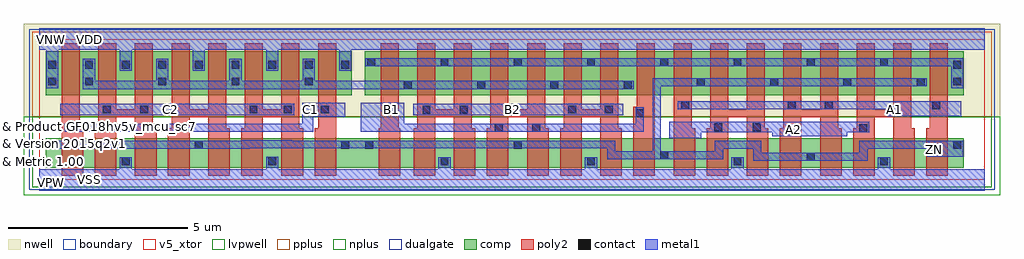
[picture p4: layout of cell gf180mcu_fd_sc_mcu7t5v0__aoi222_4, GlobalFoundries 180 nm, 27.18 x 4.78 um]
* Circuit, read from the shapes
.subckt gf180mcu_fd_sc_mcu7t5v0__aoi222_4 A1 A2 B1 B2 C1 C2 VDD VNW VSS ZN
XM1 n1 C1 ZN VSUBS nfet_05v0 w=0.82u l=0.6u
XM2 VSS C2 n1 VSUBS nfet_05v0 w=0.82u l=0.6u
XM3 n2 C2 VSS VSUBS nfet_05v0 w=0.82u l=0.6u
XM4 ZN C1 n2 VSUBS nfet_05v0 w=0.82u l=0.6u
XM5 n3 C1 ZN VSUBS nfet_05v0 w=0.82u l=0.6u
XM6 VSS C2 n3 VSUBS nfet_05v0 w=0.82u l=0.6u
XM7 n4 C2 VSS VSUBS nfet_05v0 w=0.82u l=0.6u
XM8 ZN C1 n4 VSUBS nfet_05v0 w=0.82u l=0.6u
XM9 n5 B1 ZN VSUBS nfet_05v0 w=0.82u l=0.6u
XM10 VSS B2 n5 VSUBS nfet_05v0 w=0.82u l=0.6u
XM11 n6 B2 VSS VSUBS nfet_05v0 w=0.82u l=0.6u
XM12 ZN B1 n6 VSUBS nfet_05v0 w=0.82u l=0.6u
XM13 n7 B1 ZN VSUBS nfet_05v0 w=0.82u l=0.6u
XM14 VSS B2 n7 VSUBS nfet_05v0 w=0.82u l=0.6u
XM15 n8 B2 VSS VSUBS nfet_05v0 w=0.82u l=0.6u
XM16 ZN B1 n8 VSUBS nfet_05v0 w=0.82u l=0.6u
XM17 n9 A1 ZN VSUBS nfet_05v0 w=0.82u l=0.6u
XM18 VSS A2 n9 VSUBS nfet_05v0 w=0.82u l=0.6u
XM19 n10 A2 VSS VSUBS nfet_05v0 w=0.82u l=0.6u
XM20 ZN A1 n10 VSUBS nfet_05v0 w=0.82u l=0.6u
XM21 n11 A1 ZN VSUBS nfet_05v0 w=0.82u l=0.6u
XM22 VSS A2 n11 VSUBS nfet_05v0 w=0.82u l=0.6u
XM23 n12 A2 VSS VSUBS nfet_05v0 w=0.82u l=0.6u
XM24 ZN A1 n12 VSUBS nfet_05v0 w=0.82u l=0.6u
XM25 n13 C1 VDD VNW pfet_05v0 w=1.22u l=0.5u m=4
XM26 VDD C2 n13 VNW pfet_05v0 w=1.22u l=0.5u m=4
XM27 n13 B1 n14 VNW pfet_05v0 w=1.22u l=0.5u m=4
XM28 n14 B2 n13 VNW pfet_05v0 w=1.22u l=0.5u m=4
XM29 ZN A1 n14 VNW pfet_05v0 w=1.22u l=0.5u m=4
XM30 n14 A2 ZN VNW pfet_05v0 w=1.22u l=0.5u m=4
.ends

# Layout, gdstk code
import gdstk
lib = gdstk.Library(unit=1e-6, precision=1e-09)
def R(c, l, rs):  # rectangles x0, y0, x1, y1
    for r in rs: c.add(gdstk.rectangle(r[:2], r[2:], *l))
def A(c, l, x, y, w, h, nx, ny, dx, dy):  # array of equal rectangles
    R(c, l, [(x+i*dx, y+j*dy, x+i*dx+w, y+j*dy+h) for i in range(nx) for j in range(ny)])
def P(c, l, *ps):  # polygons
    for p in ps: c.add(gdstk.Polygon(p, *l))
boundary = (0, 0)
nwell = (21, 0)
comp = (22, 0)
poly2 = (30, 0)
pplus = (31, 0)
nplus = (32, 0)
contact = (33, 0)
metal1 = (34, 0)
dualgate = (55, 0)
v5_xtor = (112, 1)
lvpwell = (204, 0)

gf180mcu_fd_sc_mcu7t5v0_ = lib.new_cell('gf180mcu_fd_sc_mcu7t5v0__aoi222_4')
R(gf180mcu_fd_sc_mcu7t5v0_, boundary, [(0,0,26.32,3.92)])
R(gf180mcu_fd_sc_mcu7t5v0_, nwell, [(-0.43,1.76,26.75,4.35)])
R(gf180mcu_fd_sc_mcu7t5v0_, comp, [(0.18,0.34,25.74,1.16), (0.18,2.36,8.7,3.58), (9.06,2.36,25.74,3.58)])
P(gf180mcu_fd_sc_mcu7t5v0_, poly2, [(0.62,0.12),(0.62,3.8),(1.12,3.8),(1.12,1.44),(1.22,1.44),(1.22,0.12)],
  [(1.54,0.12),(1.54,1.44),(1.64,1.44),(1.64,3.8),(2.14,3.8),(2.14,1.97),(2.66,1.97),(2.66,3.8),(3.16,3.8),(3.16,1.44),(3.26,1.44),(3.26,0.12),(2.66,0.12),(2.66,1.74),(2.14,1.74),(2.14,0.12)],
  [(3.58,0.12),(3.58,1.44),(3.68,1.44),(3.68,3.8),(4.18,3.8),(4.18,1.97),(4.7,1.97),(4.7,3.8),(5.2,3.8),(5.2,1.44),(5.3,1.44),(5.3,0.12),(4.7,0.12),(4.7,1.74),(4.18,1.74),(4.18,0.12)],
  [(5.62,0.12),(5.62,1.44),(5.72,1.44),(5.72,3.8),(6.22,3.8),(6.22,1.97),(6.74,1.97),(6.74,3.8),(7.24,3.8),(7.24,1.44),(7.34,1.44),(7.34,0.12),(6.74,0.12),(6.74,1.74),(6.22,1.74),(6.22,0.12)],
  [(7.66,0.12),(7.66,1.44),(7.76,1.44),(7.76,3.8),(8.26,3.8),(8.26,0.12)],
  [(9.45,0.12),(9.45,1.44),(9.5,1.44),(9.5,3.8),(10,3.8),(10,1.44),(10.05,1.44),(10.05,0.12)],
  [(10.42,0.12),(10.42,1.44),(10.52,1.44),(10.52,3.8),(11.02,3.8),(11.02,1.97),(11.54,1.97),(11.54,3.8),(12.04,3.8),(12.04,1.44),(12.14,1.44),(12.14,0.12),(11.54,0.12),(11.54,1.74),(11.02,1.74),(11.02,0.12)],
  [(12.46,0.12),(12.46,1.44),(12.56,1.44),(12.56,3.8),(13.06,3.8),(13.06,1.97),(13.58,1.97),(13.58,3.8),(14.08,3.8),(14.08,1.44),(14.18,1.44),(14.18,0.12),(13.58,0.12),(13.58,1.74),(13.06,1.74),(13.06,0.12)],
  [(14.5,0.12),(14.5,1.44),(14.6,1.44),(14.6,3.8),(15.1,3.8),(15.1,1.97),(15.62,1.97),(15.62,3.8),(16.12,3.8),(16.12,1.44),(16.22,1.44),(16.22,0.12),(15.62,0.12),(15.62,1.74),(15.1,1.74),(15.1,0.12)],
  [(16.54,0.12),(16.54,2.035),(16.64,2.035),(16.64,3.8),(17.14,3.8),(17.14,0.12)],
  [(17.66,0.12),(17.66,3.8),(18.16,3.8),(18.16,1.44),(18.26,1.44),(18.26,0.12)],
  [(18.58,0.12),(18.58,1.44),(18.68,1.44),(18.68,3.8),(19.18,3.8),(19.18,1.97),(19.7,1.97),(19.7,3.8),(20.2,3.8),(20.2,1.44),(20.3,1.44),(20.3,0.12),(19.7,0.12),(19.7,1.74),(19.18,1.74),(19.18,0.12)],
  [(20.62,0.12),(20.62,1.44),(20.72,1.44),(20.72,3.8),(21.22,3.8),(21.22,1.97),(21.74,1.97),(21.74,3.8),(22.24,3.8),(22.24,1.44),(22.34,1.44),(22.34,0.12),(21.74,0.12),(21.74,1.74),(21.22,1.74),(21.22,0.12)],
  [(22.66,0.12),(22.66,1.44),(22.76,1.44),(22.76,3.8),(23.26,3.8),(23.26,1.97),(23.78,1.97),(23.78,3.8),(24.28,3.8),(24.28,1.44),(24.38,1.44),(24.38,0.12),(23.78,0.12),(23.78,1.74),(23.26,1.74),(23.26,0.12)],
  [(24.7,0.12),(24.7,1.44),(24.8,1.44),(24.8,3.8),(25.3,3.8),(25.3,0.12)])
R(gf180mcu_fd_sc_mcu7t5v0_, pplus, [(-0.2,1.76,26.52,4.12)])
R(gf180mcu_fd_sc_mcu7t5v0_, nplus, [(-0.2,-0.2,26.52,1.76)])
A(gf180mcu_fd_sc_mcu7t5v0_, contact, 11.17, 0.41, 0.22, 0.22, 4, 1, 4.08, 0)
A(gf180mcu_fd_sc_mcu7t5v0_, contact, 0.25, 0.87, 0.22, 0.22, 3, 1, 4.08, 0)
A(gf180mcu_fd_sc_mcu7t5v0_, contact, 10.15, 2.535, 0.22, 0.22, 4, 1, 2.04, 0)
A(gf180mcu_fd_sc_mcu7t5v0_, contact, 18.31, 2.61, 0.22, 0.22, 4, 1, 2.04, 0)
A(gf180mcu_fd_sc_mcu7t5v0_, contact, 1.27, 2.63, 0.22, 0.22, 4, 1, 2.04, 0)
A(gf180mcu_fd_sc_mcu7t5v0_, contact, 0.25, 3.1, 0.22, 0.22, 9, 1, 1.02, 0)
A(gf180mcu_fd_sc_mcu7t5v0_, contact, 9.13, 3.165, 0.22, 0.22, 8, 1, 2.04, 0)
R(gf180mcu_fd_sc_mcu7t5v0_, contact, [(2.29,0.41,2.51,0.63), (6.37,0.41,6.59,0.63), (21.37,0.535,21.59,0.755), (17.29,0.575,17.51,0.795), (9.08,0.87,9.3,1.09), (13.21,0.87,13.43,1.09), (25.45,0.87,25.67,1.09), (22.83,1.33,23.05,1.55), (0.83,1.34,1.05,1.56), (3.81,1.34,4.03,1.56), (12.68,1.34,12.9,1.56), (13.73,1.34,13.95,1.56), (18.795,1.36,19.015,1.58), (19.87,1.36,20.09,1.58), (16.61,1.745,16.83,1.965), (10.67,1.845,10.89,2.065), (11.705,1.845,11.925,2.065), (1.77,1.85,1.99,2.07), (2.805,1.85,3.025,2.07), (5.85,1.85,6.07,2.07), (6.81,1.85,7.03,2.07), (7.83,1.85,8.05,2.07), (9.69,1.85,9.91,2.07), (14.73,1.85,14.95,2.07), (15.745,1.85,15.965,2.07), (17.87,1.97,18.09,2.19), (20.845,1.97,21.065,2.19), (21.87,1.97,22.09,2.19), (24.87,1.97,25.09,2.19), (0.25,2.63,0.47,2.85), (25.45,2.63,25.67,2.85), (25.45,3.1,25.67,3.32)])
R(gf180mcu_fd_sc_mcu7t5v0_, metal1, [(0.585,1.8,7.09,2.12), (10.415,1.8,16.255,2.12)])
P(gf180mcu_fd_sc_mcu7t5v0_, metal1, [(0.71,1.335),(0.71,1.565),(7.32,1.565),(7.32,2.15),(8.515,2.15),(8.515,1.76),(7.62,1.76),(7.62,1.335)],
  [(1.21,2.53),(1.21,3.38),(1.55,3.38),(1.55,2.76),(3.25,2.76),(3.25,3.38),(3.59,3.38),(3.59,2.76),(5.29,2.76),(5.29,3.38),(5.63,3.38),(5.63,2.76),(7.33,2.76),(7.33,3.38),(7.67,3.38),(7.67,2.76),(16.55,2.76),(16.55,2.53)],
  [(8.945,1.335),(8.945,2.15),(10.16,2.15),(10.16,1.565),(16.605,1.565),(16.605,2.025),(16.835,2.025),(16.835,1.335)],
  [(17.535,1.16),(17.535,1.615),(23.11,1.615),(23.11,1.325),(22.49,1.325),(22.49,1.22),(20.405,1.22),(20.405,1.325),(18.43,1.325),(18.43,1.16)],
  [(23.61,1.77),(23.61,1.965),(17.78,1.965),(17.78,2.195),(25.67,2.195),(25.67,1.77)],
  [(19.875,0.53),(19.875,0.865),(19.04,0.865),(19.04,0.57),(15.81,0.57),(15.81,0.865),(6.805,0.865),(6.805,0.87),(5.86,0.87),(5.86,0.865),(0.19,0.865),(0.19,1.095),(5.63,1.095),(5.63,1.1),(7.035,1.1),(7.035,1.095),(16.04,1.095),(16.04,0.8),(17.075,0.8),(17.075,2.835),(24.71,2.835),(24.71,2.605),(17.305,2.605),(17.305,0.8),(18.81,0.8),(18.81,1.095),(20.105,1.095),(20.105,0.76),(22.835,0.76),(22.835,1.095),(25.73,1.095),(25.73,0.65),(24.73,0.65),(24.73,0.865),(23.065,0.865),(23.065,0.53)],
  [(25.39,2.555),(25.39,3.16),(9.07,3.16),(9.07,3.39),(25.73,3.39),(25.73,2.555)],
  [(0,-0.3),(0,0.3),(2.23,0.3),(2.23,0.635),(2.57,0.635),(2.57,0.3),(6.31,0.3),(6.31,0.64),(6.65,0.64),(6.65,0.3),(11.11,0.3),(11.11,0.635),(11.45,0.635),(11.45,0.3),(15.19,0.3),(15.19,0.635),(15.53,0.635),(15.53,0.3),(19.27,0.3),(19.27,0.635),(19.61,0.635),(19.61,0.3),(23.35,0.3),(23.35,0.635),(23.69,0.635),(23.69,0.3),(26.32,0.3),(26.32,-0.3)],
  [(0.19,2.555),(0.19,3.62),(0,3.62),(0,4.22),(26.32,4.22),(26.32,3.62),(8.69,3.62),(8.69,3.04),(8.35,3.04),(8.35,3.62),(6.65,3.62),(6.65,3.04),(6.31,3.04),(6.31,3.62),(4.61,3.62),(4.61,3.04),(4.27,3.04),(4.27,3.62),(2.575,3.62),(2.575,3.04),(2.23,3.04),(2.23,3.62),(0.53,3.62),(0.53,2.555)])
R(gf180mcu_fd_sc_mcu7t5v0_, dualgate, [(-0.28,-0.28,26.6,4.2)])
R(gf180mcu_fd_sc_mcu7t5v0_, v5_xtor, [(0,0,26.32,3.92)])
R(gf180mcu_fd_sc_mcu7t5v0_, lvpwell, [(-0.43,-0.43,26.75,1.76)])
gf180mcu_fd_sc_mcu7t5v0_.add(gdstk.Label('A1', (23.8,1.96), layer=34, texttype=10))
gf180mcu_fd_sc_mcu7t5v0_.add(gdstk.Label('ZN', (24.92,0.84), layer=34, texttype=10))
gf180mcu_fd_sc_mcu7t5v0_.add(gdstk.Label('VSS', (1.4,0), layer=34, texttype=10))
gf180mcu_fd_sc_mcu7t5v0_.add(gdstk.Label('VDD', (1.4,3.92), layer=34, texttype=10))
gf180mcu_fd_sc_mcu7t5v0_.add(gdstk.Label('C2', (3.64,1.96), layer=34, texttype=10))
gf180mcu_fd_sc_mcu7t5v0_.add(gdstk.Label('C1', (7.56,1.96), layer=34, texttype=10))
gf180mcu_fd_sc_mcu7t5v0_.add(gdstk.Label('B2', (13.16,1.96), layer=34, texttype=10))
gf180mcu_fd_sc_mcu7t5v0_.add(gdstk.Label('B1', (9.8,1.96), layer=34, texttype=10))
gf180mcu_fd_sc_mcu7t5v0_.add(gdstk.Label('A2', (21,1.4), layer=34, texttype=10))
gf180mcu_fd_sc_mcu7t5v0_.add(gdstk.Label('& Vendor GLOBALFOUNDRIES', (0,2), layer=63, texttype=63))
gf180mcu_fd_sc_mcu7t5v0_.add(gdstk.Label('& Product GF018hv5v_mcu_sc7', (0,1.5), layer=63, texttype=63))
gf180mcu_fd_sc_mcu7t5v0_.add(gdstk.Label('& Version 2015q2v1', (0,1), layer=63, texttype=63))
gf180mcu_fd_sc_mcu7t5v0_.add(gdstk.Label('& Metric 1.00', (0,0.5), layer=63, texttype=63))
gf180mcu_fd_sc_mcu7t5v0_.add(gdstk.Label('VNW', (0.345,3.92), layer=21, texttype=10))
gf180mcu_fd_sc_mcu7t5v0_.add(gdstk.Label('VPW', (0.34,-0.085), layer=204, texttype=10))

lib.write_gds('gf180mcu_fd_sc_mcu7t5v0__aoi222_4.gds')
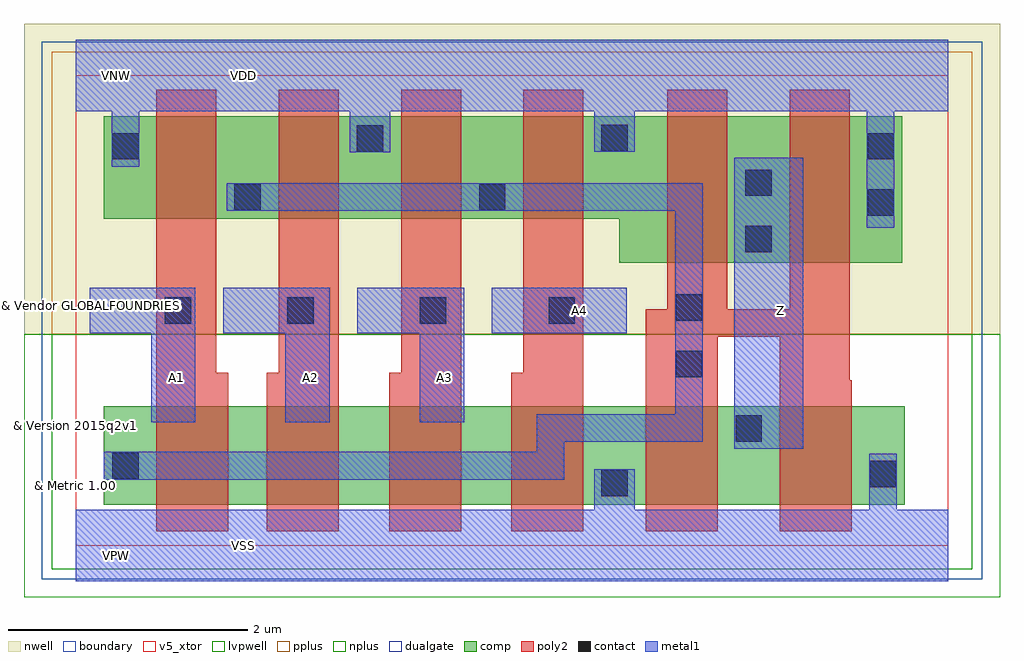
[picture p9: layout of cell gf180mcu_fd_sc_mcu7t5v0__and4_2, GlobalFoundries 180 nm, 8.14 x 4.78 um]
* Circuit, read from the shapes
.subckt gf180mcu_fd_sc_mcu7t5v0__and4_2 A1 A2 A3 A4 VDD VNW VSS Z
XM1 n1 A1 n2 VSUBS nfet_05v0 w=0.82u l=0.6u
XM2 n3 A2 n1 VSUBS nfet_05v0 w=0.82u l=0.6u
XM3 n4 A3 n3 VSUBS nfet_05v0 w=0.82u l=0.6u
XM4 VSS A4 n4 VSUBS nfet_05v0 w=0.82u l=0.6u
XM5 Z n2 VSS VSUBS nfet_05v0 w=0.82u l=0.6u m=2
XM6 n2 A1 VDD VNW pfet_05v0 w=0.855u l=0.5u
XM7 VDD A2 n2 VNW pfet_05v0 w=0.855u l=0.5u
XM8 n2 A3 VDD VNW pfet_05v0 w=0.855u l=0.5u
XM9 VDD A4 n2 VNW pfet_05v0 w=0.855u l=0.5u
XM10 Z n2 VDD VNW pfet_05v0 w=1.22u l=0.5u m=2
.ends

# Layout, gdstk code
import gdstk
lib = gdstk.Library(unit=1e-6, precision=1e-09)
def R(c, l, rs):  # rectangles x0, y0, x1, y1
    for r in rs: c.add(gdstk.rectangle(r[:2], r[2:], *l))
def P(c, l, *ps):  # polygons
    for p in ps: c.add(gdstk.Polygon(p, *l))
boundary = (0, 0)
nwell = (21, 0)
comp = (22, 0)
poly2 = (30, 0)
pplus = (31, 0)
nplus = (32, 0)
contact = (33, 0)
metal1 = (34, 0)
dualgate = (55, 0)
v5_xtor = (112, 1)
lvpwell = (204, 0)

gf180mcu_fd_sc_mcu7t5v0_ = lib.new_cell('gf180mcu_fd_sc_mcu7t5v0__and4_2')
R(gf180mcu_fd_sc_mcu7t5v0_, boundary, [(0,0,7.28,3.92)])
R(gf180mcu_fd_sc_mcu7t5v0_, nwell, [(-0.43,1.76,7.71,4.35)])
R(gf180mcu_fd_sc_mcu7t5v0_, comp, [(0.235,0.34,6.915,1.16)])
P(gf180mcu_fd_sc_mcu7t5v0_, comp, [(4.535,2.36),(4.535,2.725),(0.235,2.725),(0.235,3.58),(6.895,3.58),(6.895,2.36)])
P(gf180mcu_fd_sc_mcu7t5v0_, poly2, [(0.675,0.12),(0.675,3.8),(1.175,3.8),(1.175,1.44),(1.275,1.44),(1.275,0.12)],
  [(1.595,0.12),(1.595,1.44),(1.695,1.44),(1.695,3.8),(2.195,3.8),(2.195,0.12)],
  [(2.615,0.12),(2.615,1.44),(2.715,1.44),(2.715,3.8),(3.215,3.8),(3.215,0.12)],
  [(3.635,0.12),(3.635,1.44),(3.735,1.44),(3.735,3.8),(4.235,3.8),(4.235,0.12)],
  [(4.755,0.12),(4.755,1.97),(4.935,1.97),(4.935,3.8),(5.435,3.8),(5.435,1.97),(5.955,1.97),(5.955,3.8),(6.455,3.8),(6.455,1.38),(6.475,1.38),(6.475,0.12),(5.875,0.12),(5.875,1.74),(5.355,1.74),(5.355,0.12)])
R(gf180mcu_fd_sc_mcu7t5v0_, pplus, [(-0.2,1.76,7.48,4.12)])
R(gf180mcu_fd_sc_mcu7t5v0_, nplus, [(-0.2,-0.2,7.48,1.76)])
R(gf180mcu_fd_sc_mcu7t5v0_, contact, [(4.385,0.41,4.605,0.63), (6.625,0.485,6.845,0.705), (0.305,0.555,0.525,0.775), (5.505,0.865,5.725,1.085), (5.005,1.405,5.225,1.625), (0.745,1.85,0.965,2.07), (1.765,1.85,1.985,2.07), (2.87,1.85,3.09,2.07), (3.945,1.85,4.165,2.07), (5.005,1.875,5.225,2.095), (5.585,2.445,5.805,2.665), (6.605,2.75,6.825,2.97), (1.325,2.795,1.545,3.015), (3.365,2.795,3.585,3.015), (5.585,2.915,5.805,3.135), (0.305,3.22,0.525,3.44), (6.605,3.22,6.825,3.44), (2.345,3.285,2.565,3.505), (4.385,3.29,4.605,3.51)])
R(gf180mcu_fd_sc_mcu7t5v0_, metal1, [(5.495,0.805,6.07,3.235), (3.47,1.77,4.595,2.15)])
P(gf180mcu_fd_sc_mcu7t5v0_, metal1, [(0.63,1.03),(0.63,1.77),(0.12,1.77),(0.12,2.15),(1,2.15),(1,1.03)],
  [(1.75,1.03),(1.75,1.77),(1.23,1.77),(1.23,2.15),(2.12,2.15),(2.12,1.03)],
  [(2.87,1.03),(2.87,1.77),(2.35,1.77),(2.35,2.15),(3.24,2.15),(3.24,1.03)],
  [(0.235,0.55),(0.235,0.78),(3.845,0.78),(3.845,1.095),(5,1.095),(5,2.79),(1.26,2.79),(1.26,3.02),(5.23,3.02),(5.23,0.865),(4.075,0.865),(4.075,0.55)],
  [(0,-0.3),(0,0.3),(4.325,0.3),(4.325,0.635),(4.665,0.635),(4.665,0.3),(6.62,0.3),(6.62,0.765),(6.85,0.765),(6.85,0.3),(7.28,0.3),(7.28,-0.3)],
  [(6.6,2.65),(6.6,3.62),(4.665,3.62),(4.665,3.285),(4.325,3.285),(4.325,3.62),(2.625,3.62),(2.625,3.28),(2.285,3.28),(2.285,3.62),(0.53,3.62),(0.53,3.16),(0.3,3.16),(0.3,3.62),(0,3.62),(0,4.22),(7.28,4.22),(7.28,3.62),(6.83,3.62),(6.83,2.65)])
R(gf180mcu_fd_sc_mcu7t5v0_, dualgate, [(-0.28,-0.28,7.56,4.2)])
R(gf180mcu_fd_sc_mcu7t5v0_, v5_xtor, [(0,0,7.28,3.92)])
R(gf180mcu_fd_sc_mcu7t5v0_, lvpwell, [(-0.43,-0.43,7.71,1.76)])
gf180mcu_fd_sc_mcu7t5v0_.add(gdstk.Label('A3', (3.08,1.4), layer=34, texttype=10))
gf180mcu_fd_sc_mcu7t5v0_.add(gdstk.Label('A4', (4.2,1.96), layer=34, texttype=10))
gf180mcu_fd_sc_mcu7t5v0_.add(gdstk.Label('VDD', (1.4,3.92), layer=34, texttype=10))
gf180mcu_fd_sc_mcu7t5v0_.add(gdstk.Label('VSS', (1.4,0), layer=34, texttype=10))
gf180mcu_fd_sc_mcu7t5v0_.add(gdstk.Label('Z', (5.88,1.96), layer=34, texttype=10))
gf180mcu_fd_sc_mcu7t5v0_.add(gdstk.Label('A1', (0.84,1.4), layer=34, texttype=10))
gf180mcu_fd_sc_mcu7t5v0_.add(gdstk.Label('A2', (1.96,1.4), layer=34, texttype=10))
gf180mcu_fd_sc_mcu7t5v0_.add(gdstk.Label('& Vendor GLOBALFOUNDRIES', (0,2), layer=63, texttype=63))
gf180mcu_fd_sc_mcu7t5v0_.add(gdstk.Label('& Product GF018hv5v_mcu_sc7', (0,1.5), layer=63, texttype=63))
gf180mcu_fd_sc_mcu7t5v0_.add(gdstk.Label('& Version 2015q2v1', (0,1), layer=63, texttype=63))
gf180mcu_fd_sc_mcu7t5v0_.add(gdstk.Label('& Metric 1.00', (0,0.5), layer=63, texttype=63))
gf180mcu_fd_sc_mcu7t5v0_.add(gdstk.Label('VNW', (0.345,3.92), layer=21, texttype=10))
gf180mcu_fd_sc_mcu7t5v0_.add(gdstk.Label('VPW', (0.34,-0.085), layer=204, texttype=10))

lib.write_gds('gf180mcu_fd_sc_mcu7t5v0__and4_2.gds')
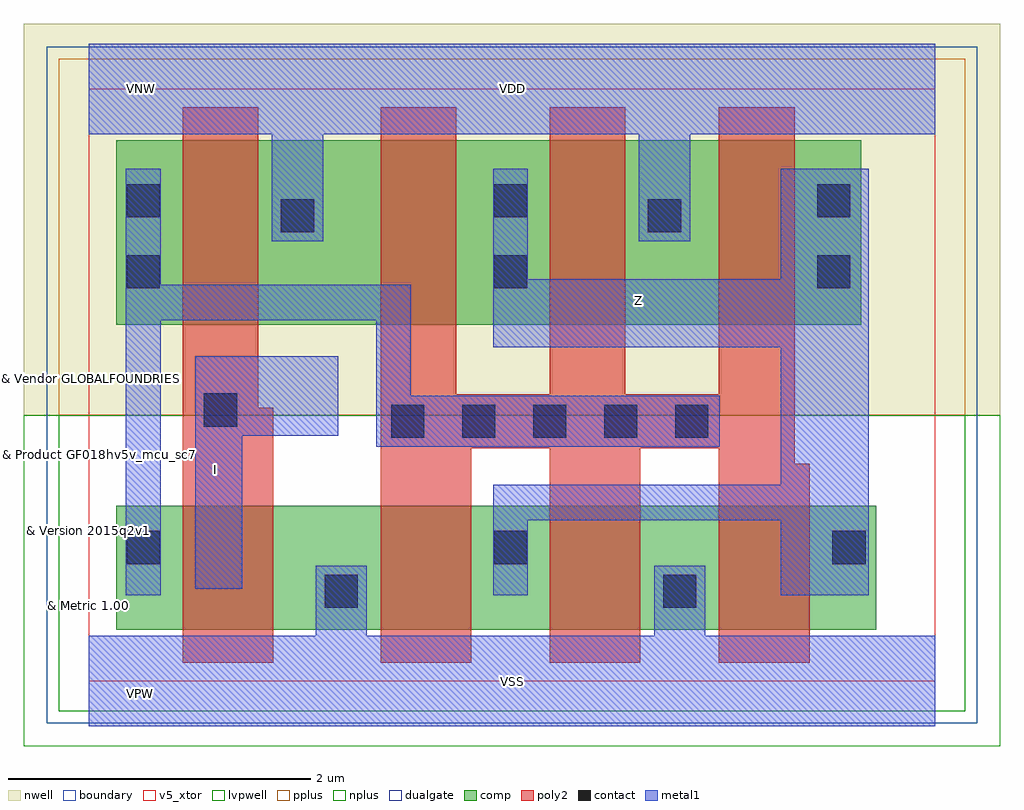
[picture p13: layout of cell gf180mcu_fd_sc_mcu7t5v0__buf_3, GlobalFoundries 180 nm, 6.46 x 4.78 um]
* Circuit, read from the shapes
.subckt gf180mcu_fd_sc_mcu7t5v0__buf_3 I VDD VNW VSS Z
XM1 VSS I n1 VSUBS nfet_05v0 w=0.82u l=0.6u
XM2 Z n1 VSS VSUBS nfet_05v0 w=0.82u l=0.6u m=3
XM3 VDD I n1 VNW pfet_05v0 w=1.22u l=0.5u
XM4 Z n1 VDD VNW pfet_05v0 w=1.22u l=0.5u m=3
.ends

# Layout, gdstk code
import gdstk
lib = gdstk.Library(unit=1e-6, precision=1e-09)
def R(c, l, rs):  # rectangles x0, y0, x1, y1
    for r in rs: c.add(gdstk.rectangle(r[:2], r[2:], *l))
def A(c, l, x, y, w, h, nx, ny, dx, dy):  # array of equal rectangles
    R(c, l, [(x+i*dx, y+j*dy, x+i*dx+w, y+j*dy+h) for i in range(nx) for j in range(ny)])
def P(c, l, *ps):  # polygons
    for p in ps: c.add(gdstk.Polygon(p, *l))
boundary = (0, 0)
nwell = (21, 0)
comp = (22, 0)
poly2 = (30, 0)
pplus = (31, 0)
nplus = (32, 0)
contact = (33, 0)
metal1 = (34, 0)
dualgate = (55, 0)
v5_xtor = (112, 1)
lvpwell = (204, 0)

gf180mcu_fd_sc_mcu7t5v0_ = lib.new_cell('gf180mcu_fd_sc_mcu7t5v0__buf_3')
R(gf180mcu_fd_sc_mcu7t5v0_, boundary, [(0,0,5.6,3.92)])
R(gf180mcu_fd_sc_mcu7t5v0_, nwell, [(-0.43,1.76,6.03,4.35)])
R(gf180mcu_fd_sc_mcu7t5v0_, comp, [(0.18,0.34,5.21,1.16), (0.18,2.36,5.11,3.58)])
P(gf180mcu_fd_sc_mcu7t5v0_, poly2, [(0.62,0.12),(0.62,3.8),(1.12,3.8),(1.12,1.81),(1.22,1.81),(1.22,0.12)],
  [(1.93,0.12),(1.93,3.8),(2.43,3.8),(2.43,1.9),(3.05,1.9),(3.05,3.8),(3.55,3.8),(3.55,1.9),(4.17,1.9),(4.17,3.8),(4.67,3.8),(4.67,1.44),(4.77,1.44),(4.77,0.12),(4.17,0.12),(4.17,1.54),(3.65,1.54),(3.65,0.12),(3.05,0.12),(3.05,1.54),(2.53,1.54),(2.53,0.12)])
R(gf180mcu_fd_sc_mcu7t5v0_, pplus, [(-0.2,1.76,5.8,4.12)])
R(gf180mcu_fd_sc_mcu7t5v0_, nplus, [(-0.2,-0.2,5.8,1.76)])
A(gf180mcu_fd_sc_mcu7t5v0_, contact, 2, 1.61, 0.22, 0.22, 5, 1, 0.47, 0)
R(gf180mcu_fd_sc_mcu7t5v0_, contact, [(1.56,0.485,1.78,0.705), (3.8,0.485,4.02,0.705), (0.25,0.775,0.47,0.995), (2.68,0.775,2.9,0.995), (4.92,0.775,5.14,0.995), (0.76,1.685,0.98,1.905), (0.25,2.6,0.47,2.82), (2.68,2.6,2.9,2.82), (4.82,2.6,5.04,2.82), (1.27,2.97,1.49,3.19), (3.7,2.97,3.92,3.19), (0.25,3.07,0.47,3.29), (2.68,3.07,2.9,3.29), (4.82,3.07,5.04,3.29)])
P(gf180mcu_fd_sc_mcu7t5v0_, metal1, [(0.705,0.61),(0.705,2.15),(1.65,2.15),(1.65,1.625),(1.015,1.625),(1.015,0.61)],
  [(0.245,0.57),(0.245,3.39),(0.475,3.39),(0.475,2.625),(2.13,2.625),(2.13,1.89),(4.175,1.89),(4.175,1.55),(1.9,1.55),(1.9,2.39),(0.475,2.39),(0.475,0.57)],
  [(2.675,0.57),(2.675,1.3),(4.58,1.3),(4.58,2.21),(2.675,2.21),(2.675,3.39),(2.905,3.39),(2.905,2.66),(4.58,2.66),(4.58,3.39),(5.16,3.39),(5.16,0.57),(4.58,0.57),(4.58,1.065),(2.905,1.065),(2.905,0.57)],
  [(0,-0.3),(0,0.3),(1.5,0.3),(1.5,0.765),(1.84,0.765),(1.84,0.3),(3.74,0.3),(3.74,0.765),(4.08,0.765),(4.08,0.3),(5.6,0.3),(5.6,-0.3)],
  [(1.21,2.91),(1.21,3.62),(0,3.62),(0,4.22),(5.6,4.22),(5.6,3.62),(3.98,3.62),(3.98,2.91),(3.64,2.91),(3.64,3.62),(1.55,3.62),(1.55,2.91)])
R(gf180mcu_fd_sc_mcu7t5v0_, dualgate, [(-0.28,-0.28,5.88,4.2)])
R(gf180mcu_fd_sc_mcu7t5v0_, v5_xtor, [(0,0,5.6,3.92)])
R(gf180mcu_fd_sc_mcu7t5v0_, lvpwell, [(-0.43,-0.43,6.03,1.76)])
gf180mcu_fd_sc_mcu7t5v0_.add(gdstk.Label('VSS', (2.8,0), layer=34, texttype=10))
gf180mcu_fd_sc_mcu7t5v0_.add(gdstk.Label('Z', (3.64,2.52), layer=34, texttype=10))
gf180mcu_fd_sc_mcu7t5v0_.add(gdstk.Label('I', (0.84,1.4), layer=34, texttype=10))
gf180mcu_fd_sc_mcu7t5v0_.add(gdstk.Label('VDD', (2.8,3.92), layer=34, texttype=10))
gf180mcu_fd_sc_mcu7t5v0_.add(gdstk.Label('& Vendor GLOBALFOUNDRIES', (0,2), layer=63, texttype=63))
gf180mcu_fd_sc_mcu7t5v0_.add(gdstk.Label('& Product GF018hv5v_mcu_sc7', (0,1.5), layer=63, texttype=63))
gf180mcu_fd_sc_mcu7t5v0_.add(gdstk.Label('& Version 2015q2v1', (0,1), layer=63, texttype=63))
gf180mcu_fd_sc_mcu7t5v0_.add(gdstk.Label('& Metric 1.00', (0,0.5), layer=63, texttype=63))
gf180mcu_fd_sc_mcu7t5v0_.add(gdstk.Label('VNW', (0.345,3.92), layer=21, texttype=10))
gf180mcu_fd_sc_mcu7t5v0_.add(gdstk.Label('VPW', (0.34,-0.085), layer=204, texttype=10))

lib.write_gds('gf180mcu_fd_sc_mcu7t5v0__buf_3.gds')
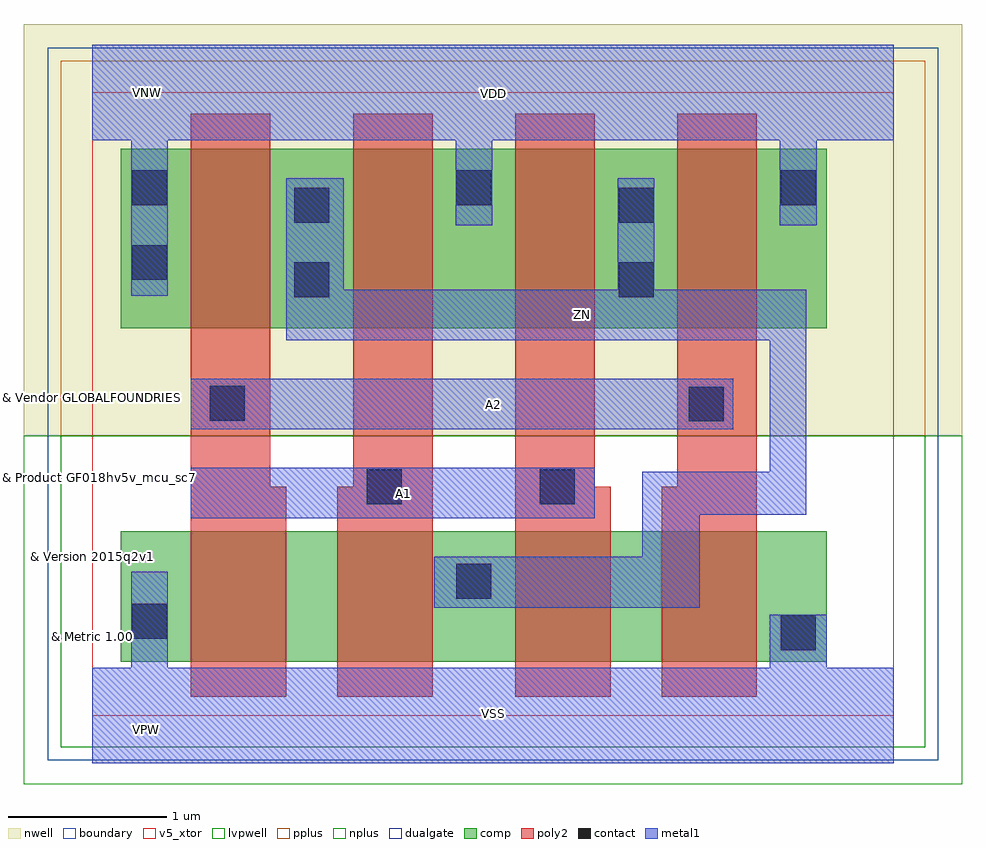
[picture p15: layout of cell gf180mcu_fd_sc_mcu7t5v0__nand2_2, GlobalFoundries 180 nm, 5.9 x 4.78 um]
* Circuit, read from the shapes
.subckt gf180mcu_fd_sc_mcu7t5v0__nand2_2 A1 A2 VDD VNW VSS ZN
XM1 n1 A2 VSS VSUBS nfet_05v0 w=0.82u l=0.6u
XM2 ZN A1 n1 VSUBS nfet_05v0 w=0.82u l=0.6u
XM3 n2 A1 ZN VSUBS nfet_05v0 w=0.82u l=0.6u
XM4 VSS A2 n2 VSUBS nfet_05v0 w=0.82u l=0.6u
XM5 ZN A2 VDD VNW pfet_05v0 w=1.13u l=0.5u m=2
XM6 VDD A1 ZN VNW pfet_05v0 w=1.13u l=0.5u m=2
.ends

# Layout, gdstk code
import gdstk
lib = gdstk.Library(unit=1e-6, precision=1e-09)
def R(c, l, rs):  # rectangles x0, y0, x1, y1
    for r in rs: c.add(gdstk.rectangle(r[:2], r[2:], *l))
def A(c, l, x, y, w, h, nx, ny, dx, dy):  # array of equal rectangles
    R(c, l, [(x+i*dx, y+j*dy, x+i*dx+w, y+j*dy+h) for i in range(nx) for j in range(ny)])
def P(c, l, *ps):  # polygons
    for p in ps: c.add(gdstk.Polygon(p, *l))
boundary = (0, 0)
nwell = (21, 0)
comp = (22, 0)
poly2 = (30, 0)
pplus = (31, 0)
nplus = (32, 0)
contact = (33, 0)
metal1 = (34, 0)
dualgate = (55, 0)
v5_xtor = (112, 1)
lvpwell = (204, 0)

gf180mcu_fd_sc_mcu7t5v0_ = lib.new_cell('gf180mcu_fd_sc_mcu7t5v0__nand2_2')
R(gf180mcu_fd_sc_mcu7t5v0_, boundary, [(0,0,5.04,3.92)])
R(gf180mcu_fd_sc_mcu7t5v0_, nwell, [(-0.43,1.76,5.47,4.35)])
R(gf180mcu_fd_sc_mcu7t5v0_, comp, [(0.18,0.34,4.62,1.16), (0.18,2.435,4.62,3.565)])
P(gf180mcu_fd_sc_mcu7t5v0_, poly2, [(0.62,0.12),(0.62,3.785),(1.12,3.785),(1.12,1.44),(1.22,1.44),(1.22,0.12)],
  [(1.54,0.12),(1.54,1.44),(1.64,1.44),(1.64,3.785),(2.14,3.785),(2.14,0.12)],
  [(2.66,0.12),(2.66,3.785),(3.16,3.785),(3.16,1.44),(3.26,1.44),(3.26,0.12)],
  [(3.58,0.12),(3.58,1.44),(3.68,1.44),(3.68,3.785),(4.18,3.785),(4.18,0.12)])
R(gf180mcu_fd_sc_mcu7t5v0_, pplus, [(-0.2,1.76,5.24,4.12)])
R(gf180mcu_fd_sc_mcu7t5v0_, nplus, [(-0.2,-0.2,5.24,1.76)])
A(gf180mcu_fd_sc_mcu7t5v0_, contact, 0.25, 3.21, 0.22, 0.22, 3, 1, 2.04, 0)
R(gf180mcu_fd_sc_mcu7t5v0_, contact, [(4.33,0.41,4.55,0.63), (0.25,0.485,0.47,0.705), (2.29,0.735,2.51,0.955), (1.725,1.33,1.945,1.55), (2.815,1.33,3.035,1.55), (3.75,1.85,3.97,2.07), (0.74,1.855,0.96,2.075), (1.27,2.63,1.49,2.85), (3.31,2.63,3.53,2.85), (0.25,2.74,0.47,2.96), (1.27,3.1,1.49,3.32), (3.31,3.1,3.53,3.32)])
R(gf180mcu_fd_sc_mcu7t5v0_, metal1, [(0.62,1.24,3.16,1.56), (0.62,1.8,4.03,2.12)])
P(gf180mcu_fd_sc_mcu7t5v0_, metal1, [(2.15,0.68),(2.15,1),(3.46,1),(3.46,1.535),(4.26,1.535),(4.26,2.36),(1.22,2.36),(1.22,3.38),(1.58,3.38),(1.58,2.68),(3.305,2.68),(3.305,3.38),(3.535,3.38),(3.535,2.68),(4.49,2.68),(4.49,1.265),(3.82,1.265),(3.82,0.68)],
  [(0,-0.3),(0,0.3),(0.245,0.3),(0.245,0.905),(0.475,0.905),(0.475,0.3),(4.26,0.3),(4.26,0.635),(4.62,0.635),(4.62,0.3),(5.04,0.3),(5.04,-0.3)],
  [(0.245,2.64),(0.245,3.62),(0,3.62),(0,4.22),(5.04,4.22),(5.04,3.62),(4.555,3.62),(4.555,3.085),(4.325,3.085),(4.325,3.62),(2.515,3.62),(2.515,3.085),(2.285,3.085),(2.285,3.62),(0.475,3.62),(0.475,2.64)])
R(gf180mcu_fd_sc_mcu7t5v0_, dualgate, [(-0.28,-0.28,5.32,4.2)])
R(gf180mcu_fd_sc_mcu7t5v0_, v5_xtor, [(0,0,5.04,3.92)])
R(gf180mcu_fd_sc_mcu7t5v0_, lvpwell, [(-0.43,-0.43,5.47,1.76)])
gf180mcu_fd_sc_mcu7t5v0_.add(gdstk.Label('VDD', (2.52,3.91), layer=34, texttype=10))
gf180mcu_fd_sc_mcu7t5v0_.add(gdstk.Label('VSS', (2.52,0.015), layer=34, texttype=10))
gf180mcu_fd_sc_mcu7t5v0_.add(gdstk.Label('ZN', (3.08,2.52), layer=34, texttype=10))
gf180mcu_fd_sc_mcu7t5v0_.add(gdstk.Label('A1', (1.96,1.4), layer=34, texttype=10))
gf180mcu_fd_sc_mcu7t5v0_.add(gdstk.Label('A2', (2.52,1.96), layer=34, texttype=10))
gf180mcu_fd_sc_mcu7t5v0_.add(gdstk.Label('& Vendor GLOBALFOUNDRIES', (0,2), layer=63, texttype=63))
gf180mcu_fd_sc_mcu7t5v0_.add(gdstk.Label('& Product GF018hv5v_mcu_sc7', (0,1.5), layer=63, texttype=63))
gf180mcu_fd_sc_mcu7t5v0_.add(gdstk.Label('& Version 2015q2v1', (0,1), layer=63, texttype=63))
gf180mcu_fd_sc_mcu7t5v0_.add(gdstk.Label('& Metric 1.00', (0,0.5), layer=63, texttype=63))
gf180mcu_fd_sc_mcu7t5v0_.add(gdstk.Label('VNW', (0.345,3.92), layer=21, texttype=10))
gf180mcu_fd_sc_mcu7t5v0_.add(gdstk.Label('VPW', (0.34,-0.085), layer=204, texttype=10))

lib.write_gds('gf180mcu_fd_sc_mcu7t5v0__nand2_2.gds')
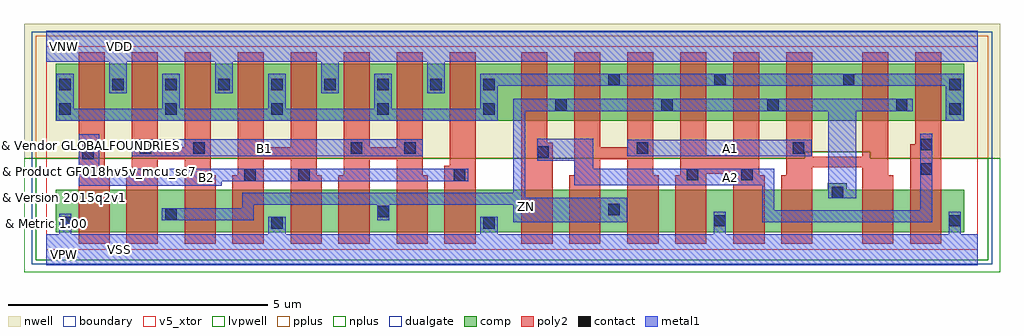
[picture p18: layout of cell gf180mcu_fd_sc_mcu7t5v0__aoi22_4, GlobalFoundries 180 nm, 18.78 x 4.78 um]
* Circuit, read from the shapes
.subckt gf180mcu_fd_sc_mcu7t5v0__aoi22_4 A1 A2 B1 B2 VDD VNW VSS ZN
XM1 n1 B2 VSS VSUBS nfet_05v0 w=0.82u l=0.6u
XM2 ZN B1 n1 VSUBS nfet_05v0 w=0.82u l=0.6u
XM3 n2 B1 ZN VSUBS nfet_05v0 w=0.82u l=0.6u
XM4 VSS B2 n2 VSUBS nfet_05v0 w=0.82u l=0.6u
XM5 n3 B2 VSS VSUBS nfet_05v0 w=0.82u l=0.6u
XM6 ZN B1 n3 VSUBS nfet_05v0 w=0.82u l=0.6u
XM7 n4 B1 ZN VSUBS nfet_05v0 w=0.82u l=0.6u
XM8 VSS B2 n4 VSUBS nfet_05v0 w=0.82u l=0.6u
XM9 n5 A2 VSS VSUBS nfet_05v0 w=0.82u l=0.6u
XM10 ZN A1 n5 VSUBS nfet_05v0 w=0.82u l=0.6u
XM11 n6 A1 ZN VSUBS nfet_05v0 w=0.82u l=0.6u
XM12 VSS A2 n6 VSUBS nfet_05v0 w=0.82u l=0.6u
XM13 n7 A2 VSS VSUBS nfet_05v0 w=0.82u l=0.6u
XM14 ZN A1 n7 VSUBS nfet_05v0 w=0.82u l=0.6u
XM15 n8 A1 ZN VSUBS nfet_05v0 w=0.82u l=0.6u
XM16 VSS A2 n8 VSUBS nfet_05v0 w=0.82u l=0.6u
XM17 VDD B2 n9 VNW pfet_05v0 w=1.095u l=0.5u m=4
XM18 n9 B1 VDD VNW pfet_05v0 w=1.095u l=0.5u m=4
XM19 ZN A2 n9 VNW pfet_05v0 w=1.095u l=0.5u m=4
XM20 n9 A1 ZN VNW pfet_05v0 w=1.095u l=0.5u m=4
.ends

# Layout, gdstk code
import gdstk
lib = gdstk.Library(unit=1e-6, precision=1e-09)
def R(c, l, rs):  # rectangles x0, y0, x1, y1
    for r in rs: c.add(gdstk.rectangle(r[:2], r[2:], *l))
def A(c, l, x, y, w, h, nx, ny, dx, dy):  # array of equal rectangles
    R(c, l, [(x+i*dx, y+j*dy, x+i*dx+w, y+j*dy+h) for i in range(nx) for j in range(ny)])
def P(c, l, *ps):  # polygons
    for p in ps: c.add(gdstk.Polygon(p, *l))
boundary = (0, 0)
nwell = (21, 0)
comp = (22, 0)
poly2 = (30, 0)
pplus = (31, 0)
nplus = (32, 0)
contact = (33, 0)
metal1 = (34, 0)
dualgate = (55, 0)
v5_xtor = (112, 1)
lvpwell = (204, 0)

gf180mcu_fd_sc_mcu7t5v0_ = lib.new_cell('gf180mcu_fd_sc_mcu7t5v0__aoi22_4')
R(gf180mcu_fd_sc_mcu7t5v0_, boundary, [(0,0,17.92,3.92)])
P(gf180mcu_fd_sc_mcu7t5v0_, nwell, [(-0.43,1.76),(-0.43,4.35),(18.35,4.35),(18.35,1.76),(15.855,1.76),(15.855,1.885),(14.595,1.885),(14.595,1.76)])
R(gf180mcu_fd_sc_mcu7t5v0_, comp, [(0.18,2.485,17.66,3.58)])
P(gf180mcu_fd_sc_mcu7t5v0_, comp, [(0.18,0.34),(0.18,1.16),(15.04,1.16),(15.04,1.285),(15.4,1.285),(15.4,1.16),(17.66,1.16),(17.66,0.34)])
P(gf180mcu_fd_sc_mcu7t5v0_, poly2, [(0.62,0.12),(0.62,3.8),(1.12,3.8),(1.12,1.44),(1.22,1.44),(1.22,0.12)],
  [(1.54,0.12),(1.54,1.44),(1.64,1.44),(1.64,3.8),(2.14,3.8),(2.14,1.97),(2.66,1.97),(2.66,3.8),(3.16,3.8),(3.16,1.44),(3.26,1.44),(3.26,0.12),(2.66,0.12),(2.66,1.74),(2.14,1.74),(2.14,0.12)],
  [(3.58,0.12),(3.58,1.44),(3.68,1.44),(3.68,3.8),(4.18,3.8),(4.18,1.97),(4.7,1.97),(4.7,3.8),(5.2,3.8),(5.2,1.44),(5.3,1.44),(5.3,0.12),(4.7,0.12),(4.7,1.74),(4.18,1.74),(4.18,0.12)],
  [(5.62,0.12),(5.62,1.44),(5.72,1.44),(5.72,3.8),(6.22,3.8),(6.22,1.97),(6.74,1.97),(6.74,3.8),(7.24,3.8),(7.24,1.44),(7.34,1.44),(7.34,0.12),(6.74,0.12),(6.74,1.74),(6.22,1.74),(6.22,0.12)],
  [(7.66,0.12),(7.66,1.62),(7.76,1.62),(7.76,3.8),(8.26,3.8),(8.26,0.12)],
  [(9.14,0.12),(9.14,3.8),(9.64,3.8),(9.64,2.06),(9.74,2.06),(9.74,0.12)],
  [(10.06,0.12),(10.06,1.44),(10.16,1.44),(10.16,3.8),(10.66,3.8),(10.66,1.97),(11.18,1.97),(11.18,3.8),(11.68,3.8),(11.68,1.44),(11.78,1.44),(11.78,0.12),(11.18,0.12),(11.18,1.74),(10.66,1.74),(10.66,0.12)],
  [(12.1,0.12),(12.1,1.44),(12.2,1.44),(12.2,3.8),(12.7,3.8),(12.7,1.825),(13.22,1.825),(13.22,3.8),(13.72,3.8),(13.72,1.44),(13.82,1.44),(13.82,0.12),(13.22,0.12),(13.22,1.46),(12.7,1.46),(12.7,0.12)],
  [(14.14,0.12),(14.14,1.44),(14.24,1.44),(14.24,3.8),(14.74,3.8),(14.74,1.79),(15.7,1.79),(15.7,3.8),(16.2,3.8),(16.2,1.44),(16.3,1.44),(16.3,0.12),(15.7,0.12),(15.7,1.59),(14.74,1.59),(14.74,0.12)],
  [(16.62,0.12),(16.62,2.035),(16.72,2.035),(16.72,3.8),(17.22,3.8),(17.22,0.12)])
P(gf180mcu_fd_sc_mcu7t5v0_, pplus, [(-0.2,1.76),(-0.2,4.12),(18.12,4.12),(18.12,1.76),(15.855,1.76),(15.855,1.885),(14.595,1.885),(14.595,1.76)])
P(gf180mcu_fd_sc_mcu7t5v0_, nplus, [(-0.2,-0.2),(-0.2,1.76),(14.595,1.76),(14.595,1.885),(15.855,1.885),(15.855,1.76),(18.12,1.76),(18.12,-0.2)])
A(gf180mcu_fd_sc_mcu7t5v0_, contact, 0.25, 2.6, 0.22, 0.22, 5, 1, 2.04, 0)
A(gf180mcu_fd_sc_mcu7t5v0_, contact, 9.79, 2.68, 0.22, 0.22, 3, 1, 2.04, 0)
A(gf180mcu_fd_sc_mcu7t5v0_, contact, 0.25, 3.07, 0.22, 0.22, 9, 1, 1.02, 0)
R(gf180mcu_fd_sc_mcu7t5v0_, contact, [(4.33,0.41,4.55,0.63), (8.41,0.41,8.63,0.63), (0.25,0.415,0.47,0.635), (12.85,0.45,13.07,0.67), (17.37,0.45,17.59,0.67), (2.29,0.575,2.51,0.795), (6.37,0.63,6.59,0.85), (10.81,0.665,11.03,0.885), (15.11,0.995,15.33,1.215), (3.81,1.33,4.03,1.55), (4.85,1.33,5.07,1.55), (7.84,1.33,8.06,1.55), (12.325,1.335,12.545,1.555), (13.37,1.335,13.59,1.555), (16.825,1.445,17.045,1.665), (0.69,1.745,0.91,1.965), (9.45,1.77,9.67,1.99), (1.8,1.85,2.02,2.07), (2.83,1.85,3.05,2.07), (5.855,1.85,6.075,2.07), (6.89,1.85,7.11,2.07), (11.365,1.85,11.585,2.07), (14.365,1.85,14.585,2.07), (16.825,1.915,17.045,2.135), (17.37,2.6,17.59,2.82), (16.35,2.68,16.57,2.9), (17.37,3.07,17.59,3.29), (10.81,3.165,11.03,3.385), (12.85,3.165,13.07,3.385), (15.33,3.165,15.55,3.385)])
R(gf180mcu_fd_sc_mcu7t5v0_, metal1, [(1.64,1.8,7.24,2.13), (11.18,1.8,14.73,2.12)])
P(gf180mcu_fd_sc_mcu7t5v0_, metal1, [(0.62,1.23),(0.62,2.225),(1.02,2.225),(1.02,1.56),(8.12,1.56),(8.12,1.325),(3.375,1.325),(3.375,1.23)],
  [(8.985,0.53),(8.985,0.865),(6.595,0.865),(6.595,0.57),(6.365,0.57),(6.365,0.865),(3.995,0.865),(3.995,0.57),(2.225,0.57),(2.225,0.8),(3.765,0.8),(3.765,1.095),(8.985,1.095),(8.985,2.91),(16.67,2.91),(16.67,2.67),(15.58,2.67),(15.58,0.99),(15.05,0.99),(15.05,2.67),(9.215,2.67),(9.215,1),(11.18,1),(11.18,0.53)],
  [(13.78,0.53),(13.78,1.24),(10.16,1.24),(10.16,1.71),(9.445,1.71),(9.445,2.14),(10.52,2.14),(10.52,1.56),(14.01,1.56),(14.01,0.76),(16.82,0.76),(16.82,2.235),(17.05,2.235),(17.05,0.53)],
  [(0.19,2.485),(0.19,3.39),(0.53,3.39),(0.53,2.715),(2.23,2.715),(2.23,3.39),(2.57,3.39),(2.57,2.715),(4.27,2.715),(4.27,3.39),(4.61,3.39),(4.61,2.715),(6.31,2.715),(6.31,3.39),(6.65,3.39),(6.65,2.715),(8.35,2.715),(8.35,3.39),(17.65,3.39),(17.65,2.485),(17.31,2.485),(17.31,3.16),(8.69,3.16),(8.69,2.485)],
  [(0,-0.3),(0,0.3),(0.245,0.3),(0.245,0.695),(0.475,0.695),(0.475,0.3),(4.27,0.3),(4.27,0.635),(4.61,0.635),(4.61,0.3),(8.35,0.3),(8.35,0.635),(8.69,0.635),(8.69,0.3),(12.845,0.3),(12.845,0.73),(13.075,0.73),(13.075,0.3),(17.365,0.3),(17.365,0.73),(17.595,0.73),(17.595,0.3),(17.92,0.3),(17.92,-0.3)],
  [(1.21,3.01),(1.21,3.62),(0,3.62),(0,4.22),(17.92,4.22),(17.92,3.62),(7.67,3.62),(7.67,3.01),(7.33,3.01),(7.33,3.62),(5.63,3.62),(5.63,3.01),(5.29,3.01),(5.29,3.62),(3.59,3.62),(3.59,3.01),(3.25,3.01),(3.25,3.62),(1.55,3.62),(1.55,3.01)])
R(gf180mcu_fd_sc_mcu7t5v0_, dualgate, [(-0.28,-0.28,18.2,4.2)])
R(gf180mcu_fd_sc_mcu7t5v0_, v5_xtor, [(0,0,17.92,3.92)])
P(gf180mcu_fd_sc_mcu7t5v0_, lvpwell, [(-0.43,-0.43),(-0.43,1.76),(14.595,1.76),(14.595,1.885),(15.855,1.885),(15.855,1.76),(18.35,1.76),(18.35,-0.43)])
gf180mcu_fd_sc_mcu7t5v0_.add(gdstk.Label('A2', (13.16,1.4), layer=34, texttype=10))
gf180mcu_fd_sc_mcu7t5v0_.add(gdstk.Label('B1', (4.2,1.96), layer=34, texttype=10))
gf180mcu_fd_sc_mcu7t5v0_.add(gdstk.Label('B2', (3.08,1.4), layer=34, texttype=10))
gf180mcu_fd_sc_mcu7t5v0_.add(gdstk.Label('VDD', (1.4,3.92), layer=34, texttype=10))
gf180mcu_fd_sc_mcu7t5v0_.add(gdstk.Label('VSS', (1.4,0), layer=34, texttype=10))
gf180mcu_fd_sc_mcu7t5v0_.add(gdstk.Label('ZN', (9.24,0.84), layer=34, texttype=10))
gf180mcu_fd_sc_mcu7t5v0_.add(gdstk.Label('A1', (13.16,1.96), layer=34, texttype=10))
gf180mcu_fd_sc_mcu7t5v0_.add(gdstk.Label('& Vendor GLOBALFOUNDRIES', (0,2), layer=63, texttype=63))
gf180mcu_fd_sc_mcu7t5v0_.add(gdstk.Label('& Product GF018hv5v_mcu_sc7', (0,1.5), layer=63, texttype=63))
gf180mcu_fd_sc_mcu7t5v0_.add(gdstk.Label('& Version 2015q2v1', (0,1), layer=63, texttype=63))
gf180mcu_fd_sc_mcu7t5v0_.add(gdstk.Label('& Metric 1.00', (0,0.5), layer=63, texttype=63))
gf180mcu_fd_sc_mcu7t5v0_.add(gdstk.Label('VNW', (0.345,3.92), layer=21, texttype=10))
gf180mcu_fd_sc_mcu7t5v0_.add(gdstk.Label('VPW', (0.34,-0.085), layer=204, texttype=10))

lib.write_gds('gf180mcu_fd_sc_mcu7t5v0__aoi22_4.gds')
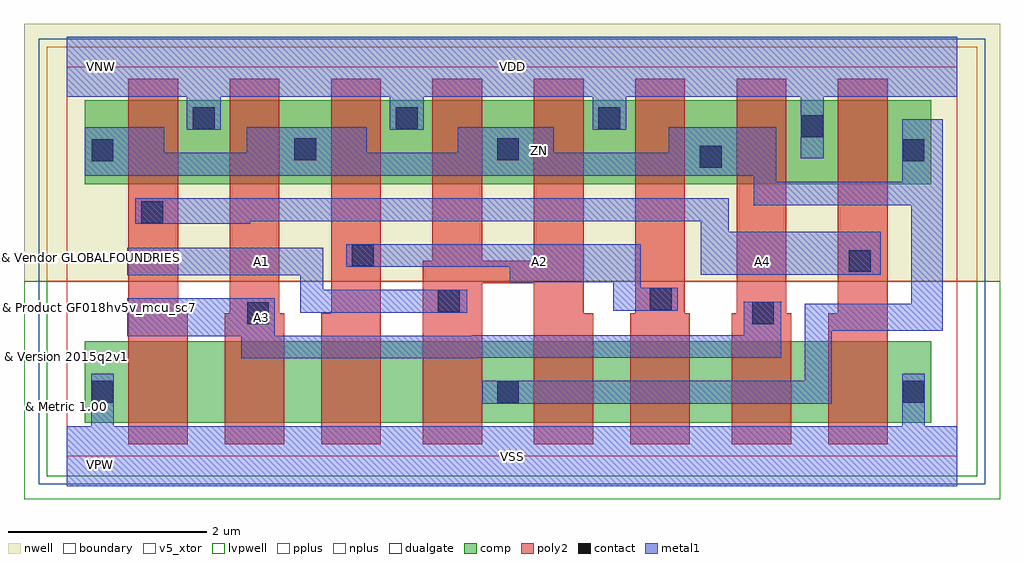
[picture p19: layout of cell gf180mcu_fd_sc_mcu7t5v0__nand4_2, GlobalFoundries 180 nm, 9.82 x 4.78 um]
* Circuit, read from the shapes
.subckt gf180mcu_fd_sc_mcu7t5v0__nand4_2 A1 A2 A3 A4 VDD VNW VSS ZN
XM1 n1 A4 VSS VSUBS nfet_05v0 w=0.82u l=0.6u
XM2 n2 A3 n1 VSUBS nfet_05v0 w=0.82u l=0.6u
XM3 n3 A2 n2 VSUBS nfet_05v0 w=0.82u l=0.6u
XM4 ZN A1 n3 VSUBS nfet_05v0 w=0.82u l=0.6u
XM5 n4 A1 ZN VSUBS nfet_05v0 w=0.82u l=0.6u
XM6 n5 A2 n4 VSUBS nfet_05v0 w=0.82u l=0.6u
XM7 n6 A3 n5 VSUBS nfet_05v0 w=0.82u l=0.6u
XM8 VSS A4 n6 VSUBS nfet_05v0 w=0.82u l=0.6u
XM9 VDD A4 ZN VNW pfet_05v0 w=0.845u l=0.5u m=2
XM10 ZN A3 VDD VNW pfet_05v0 w=0.845u l=0.5u m=2
XM11 VDD A2 ZN VNW pfet_05v0 w=0.845u l=0.5u m=2
XM12 ZN A1 VDD VNW pfet_05v0 w=0.845u l=0.5u m=2
.ends

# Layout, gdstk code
import gdstk
lib = gdstk.Library(unit=1e-6, precision=1e-09)
def R(c, l, rs):  # rectangles x0, y0, x1, y1
    for r in rs: c.add(gdstk.rectangle(r[:2], r[2:], *l))
def A(c, l, x, y, w, h, nx, ny, dx, dy):  # array of equal rectangles
    R(c, l, [(x+i*dx, y+j*dy, x+i*dx+w, y+j*dy+h) for i in range(nx) for j in range(ny)])
def P(c, l, *ps):  # polygons
    for p in ps: c.add(gdstk.Polygon(p, *l))
boundary = (0, 0)
nwell = (21, 0)
comp = (22, 0)
poly2 = (30, 0)
pplus = (31, 0)
nplus = (32, 0)
contact = (33, 0)
metal1 = (34, 0)
dualgate = (55, 0)
v5_xtor = (112, 1)
lvpwell = (204, 0)

gf180mcu_fd_sc_mcu7t5v0_ = lib.new_cell('gf180mcu_fd_sc_mcu7t5v0__nand4_2')
R(gf180mcu_fd_sc_mcu7t5v0_, boundary, [(0,0,8.96,3.92)])
R(gf180mcu_fd_sc_mcu7t5v0_, nwell, [(-0.43,1.76,9.39,4.35)])
R(gf180mcu_fd_sc_mcu7t5v0_, comp, [(0.18,0.34,8.7,1.16), (0.18,2.735,8.7,3.58)])
P(gf180mcu_fd_sc_mcu7t5v0_, poly2, [(0.62,0.12),(0.62,3.8),(1.12,3.8),(1.12,1.44),(1.22,1.44),(1.22,0.12)],
  [(1.59,0.12),(1.59,1.44),(1.64,1.44),(1.64,3.8),(2.14,3.8),(2.14,1.44),(2.19,1.44),(2.19,0.12)],
  [(2.56,0.12),(2.56,1.44),(2.66,1.44),(2.66,3.8),(3.16,3.8),(3.16,0.12)],
  [(3.58,0.12),(3.58,1.97),(3.68,1.97),(3.68,3.8),(4.18,3.8),(4.18,1.97),(4.7,1.97),(4.7,3.8),(5.2,3.8),(5.2,1.44),(5.3,1.44),(5.3,0.12),(4.7,0.12),(4.7,1.74),(4.18,1.74),(4.18,0.12)],
  [(5.67,0.12),(5.67,1.44),(5.72,1.44),(5.72,3.8),(6.22,3.8),(6.22,1.44),(6.27,1.44),(6.27,0.12)],
  [(6.69,0.12),(6.69,1.44),(6.74,1.44),(6.74,3.8),(7.24,3.8),(7.24,1.44),(7.29,1.44),(7.29,0.12)],
  [(7.66,0.12),(7.66,1.44),(7.76,1.44),(7.76,3.8),(8.26,3.8),(8.26,0.12)])
R(gf180mcu_fd_sc_mcu7t5v0_, pplus, [(-0.2,1.76,9.16,4.12)])
R(gf180mcu_fd_sc_mcu7t5v0_, nplus, [(-0.2,-0.2,9.16,1.76)])
A(gf180mcu_fd_sc_mcu7t5v0_, contact, 1.27, 3.29, 0.22, 0.22, 3, 1, 2.04, 0)
R(gf180mcu_fd_sc_mcu7t5v0_, contact, [(4.33,0.535,4.55,0.755), (0.25,0.54,0.47,0.76), (8.41,0.54,8.63,0.76), (1.815,1.33,2.035,1.55), (6.895,1.33,7.115,1.55), (3.735,1.45,3.955,1.67), (5.865,1.47,6.085,1.69), (7.87,1.855,8.09,2.075), (2.87,1.91,3.09,2.13), (0.75,2.345,0.97,2.565), (6.37,2.905,6.59,3.125), (0.25,2.97,0.47,3.19), (8.41,2.97,8.63,3.19), (2.29,2.98,2.51,3.2), (4.33,2.98,4.55,3.2), (7.39,3.21,7.61,3.43)])
P(gf180mcu_fd_sc_mcu7t5v0_, metal1, [(2.35,1.445),(2.35,1.82),(0.61,1.82),(0.61,2.1),(2.58,2.1),(2.58,1.675),(4.03,1.675),(4.03,1.445)],
  [(5.5,1.465),(5.5,1.75),(4.455,1.75),(4.455,1.905),(2.81,1.905),(2.81,2.135),(5.775,2.135),(5.775,1.695),(6.15,1.695),(6.15,1.465)],
  [(1.755,0.985),(1.755,1.21),(0.61,1.21),(0.61,1.59),(2.095,1.59),(2.095,1.215),(4.08,1.215),(4.08,1.22),(6.81,1.22),(6.81,1.555),(7.19,1.555),(7.19,0.99),(4.13,0.99),(4.13,0.985)],
  [(6.38,1.825),(6.38,2.365),(1.845,2.365),(1.845,2.34),(0.69,2.34),(0.69,2.595),(6.66,2.595),(6.66,2.26),(8.19,2.26),(8.19,1.825)],
  [(4.18,0.53),(4.18,0.76),(7.425,0.76),(7.425,1.535),(8.495,1.535),(8.495,2.525),(6.91,2.525),(6.91,2.825),(0.18,2.825),(0.18,3.31),(0.98,3.31),(0.98,3.055),(1.81,3.055),(1.81,3.31),(3.02,3.31),(3.02,3.055),(3.935,3.055),(3.935,3.31),(4.9,3.31),(4.9,3.055),(6.055,3.055),(6.055,3.31),(7.14,3.31),(7.14,2.76),(8.405,2.76),(8.405,3.39),(8.815,3.39),(8.815,1.265),(7.695,1.265),(7.695,0.53)],
  [(0,-0.3),(0,0.3),(0.245,0.3),(0.245,0.83),(0.475,0.83),(0.475,0.3),(8.405,0.3),(8.405,0.83),(8.635,0.83),(8.635,0.3),(8.96,0.3),(8.96,-0.3)],
  [(7.385,3),(7.385,3.62),(5.63,3.62),(5.63,3.285),(5.29,3.285),(5.29,3.62),(3.59,3.62),(3.59,3.285),(3.25,3.285),(3.25,3.62),(1.55,3.62),(1.55,3.285),(1.21,3.285),(1.21,3.62),(0,3.62),(0,4.22),(8.96,4.22),(8.96,3.62),(7.615,3.62),(7.615,3)])
R(gf180mcu_fd_sc_mcu7t5v0_, dualgate, [(-0.28,-0.28,9.24,4.2)])
R(gf180mcu_fd_sc_mcu7t5v0_, v5_xtor, [(0,0,8.96,3.92)])
R(gf180mcu_fd_sc_mcu7t5v0_, lvpwell, [(-0.43,-0.43,9.39,1.76)])
gf180mcu_fd_sc_mcu7t5v0_.add(gdstk.Label('A3', (1.96,1.4), layer=34, texttype=10))
gf180mcu_fd_sc_mcu7t5v0_.add(gdstk.Label('A4', (7,1.96), layer=34, texttype=10))
gf180mcu_fd_sc_mcu7t5v0_.add(gdstk.Label('VDD', (4.48,3.925), layer=34, texttype=10))
gf180mcu_fd_sc_mcu7t5v0_.add(gdstk.Label('VSS', (4.48,0), layer=34, texttype=10))
gf180mcu_fd_sc_mcu7t5v0_.add(gdstk.Label('ZN', (4.76,3.08), layer=34, texttype=10))
gf180mcu_fd_sc_mcu7t5v0_.add(gdstk.Label('A1', (1.96,1.96), layer=34, texttype=10))
gf180mcu_fd_sc_mcu7t5v0_.add(gdstk.Label('A2', (4.76,1.96), layer=34, texttype=10))
gf180mcu_fd_sc_mcu7t5v0_.add(gdstk.Label('& Vendor GLOBALFOUNDRIES', (0,2), layer=63, texttype=63))
gf180mcu_fd_sc_mcu7t5v0_.add(gdstk.Label('& Product GF018hv5v_mcu_sc7', (0,1.5), layer=63, texttype=63))
gf180mcu_fd_sc_mcu7t5v0_.add(gdstk.Label('& Version 2015q2v1', (0,1), layer=63, texttype=63))
gf180mcu_fd_sc_mcu7t5v0_.add(gdstk.Label('& Metric 1.00', (0,0.5), layer=63, texttype=63))
gf180mcu_fd_sc_mcu7t5v0_.add(gdstk.Label('VNW', (0.345,3.92), layer=21, texttype=10))
gf180mcu_fd_sc_mcu7t5v0_.add(gdstk.Label('VPW', (0.34,-0.085), layer=204, texttype=10))

lib.write_gds('gf180mcu_fd_sc_mcu7t5v0__nand4_2.gds')
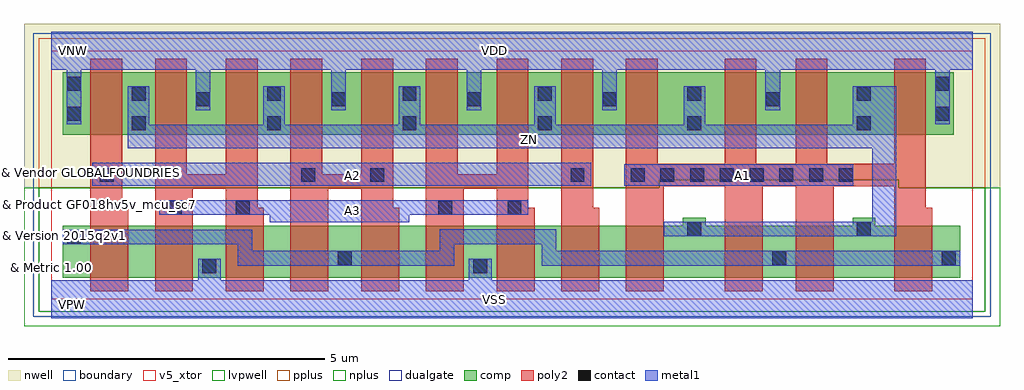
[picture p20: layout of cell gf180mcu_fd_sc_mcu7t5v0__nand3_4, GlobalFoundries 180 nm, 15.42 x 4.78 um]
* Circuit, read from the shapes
.subckt gf180mcu_fd_sc_mcu7t5v0__nand3_4 A1 A2 A3 VDD VNW VSS ZN
XM1 n1 A2 n2 VSUBS nfet_05v0 w=0.82u l=0.6u
XM2 VSS A3 n1 VSUBS nfet_05v0 w=0.82u l=0.6u
XM3 n3 A3 VSS VSUBS nfet_05v0 w=0.82u l=0.6u
XM4 n2 A2 n3 VSUBS nfet_05v0 w=0.82u l=0.6u
XM5 n4 A2 n2 VSUBS nfet_05v0 w=0.82u l=0.6u
XM6 VSS A3 n4 VSUBS nfet_05v0 w=0.82u l=0.6u
XM7 n5 A3 VSS VSUBS nfet_05v0 w=0.82u l=0.6u
XM8 n6 A2 n5 VSUBS nfet_05v0 w=0.82u l=0.6u
XM9 ZN A1 n6 VSUBS nfet_05v0 w=0.82u l=0.6u
XM10 n2 A1 ZN VSUBS nfet_05v0 w=0.82u l=0.6u m=3
XM11 ZN A2 VDD VNW pfet_05v0 w=0.985u l=0.5u m=4
XM12 VDD A3 ZN VNW pfet_05v0 w=0.985u l=0.5u m=4
XM13 ZN A1 VDD VNW pfet_05v0 w=0.985u l=0.5u m=4
.ends

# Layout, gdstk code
import gdstk
lib = gdstk.Library(unit=1e-6, precision=1e-09)
def R(c, l, rs):  # rectangles x0, y0, x1, y1
    for r in rs: c.add(gdstk.rectangle(r[:2], r[2:], *l))
def A(c, l, x, y, w, h, nx, ny, dx, dy):  # array of equal rectangles
    R(c, l, [(x+i*dx, y+j*dy, x+i*dx+w, y+j*dy+h) for i in range(nx) for j in range(ny)])
def P(c, l, *ps):  # polygons
    for p in ps: c.add(gdstk.Polygon(p, *l))
boundary = (0, 0)
nwell = (21, 0)
comp = (22, 0)
poly2 = (30, 0)
pplus = (31, 0)
nplus = (32, 0)
contact = (33, 0)
metal1 = (34, 0)
dualgate = (55, 0)
v5_xtor = (112, 1)
lvpwell = (204, 0)

gf180mcu_fd_sc_mcu7t5v0_ = lib.new_cell('gf180mcu_fd_sc_mcu7t5v0__nand3_4')
R(gf180mcu_fd_sc_mcu7t5v0_, boundary, [(0,0,14.56,3.92)])
P(gf180mcu_fd_sc_mcu7t5v0_, nwell, [(-0.43,1.76),(-0.43,4.35),(14.99,4.35),(14.99,1.76),(13.39,1.76),(13.39,1.885),(9.61,1.885),(9.61,1.76)])
R(gf180mcu_fd_sc_mcu7t5v0_, comp, [(0.18,2.595,14.26,3.58)])
P(gf180mcu_fd_sc_mcu7t5v0_, comp, [(0.18,0.34),(0.18,1.16),(9.98,1.16),(9.98,1.285),(10.34,1.285),(10.34,1.16),(12.66,1.16),(12.66,1.285),(13.02,1.285),(13.02,1.16),(14.36,1.16),(14.36,0.34)])
P(gf180mcu_fd_sc_mcu7t5v0_, poly2, [(0.62,0.12),(0.62,3.8),(1.12,3.8),(1.12,1.44),(1.22,1.44),(1.22,0.12)],
  [(1.64,0.12),(1.64,3.8),(2.14,3.8),(2.14,1.97),(2.76,1.97),(2.76,3.8),(3.26,3.8),(3.26,1.44),(3.36,1.44),(3.36,0.12),(2.76,0.12),(2.76,1.74),(2.24,1.74),(2.24,0.12)],
  [(3.78,0.12),(3.78,3.8),(4.28,3.8),(4.28,1.97),(4.9,1.97),(4.9,3.8),(5.4,3.8),(5.4,1.44),(5.5,1.44),(5.5,0.12),(4.9,0.12),(4.9,1.74),(4.38,1.74),(4.38,0.12)],
  [(5.92,0.12),(5.92,3.8),(6.42,3.8),(6.42,1.97),(7.04,1.97),(7.04,3.8),(7.54,3.8),(7.54,1.44),(7.64,1.44),(7.64,0.12),(7.04,0.12),(7.04,1.74),(6.52,1.74),(6.52,0.12)],
  [(8.06,0.12),(8.06,3.8),(8.56,3.8),(8.56,1.44),(8.66,1.44),(8.66,0.12)],
  [(9.08,0.12),(9.08,3.8),(9.58,3.8),(9.58,2.14),(10.64,2.14),(10.64,3.8),(11.14,3.8),(11.14,2.14),(11.76,2.14),(11.76,3.8),(12.26,3.8),(12.26,2.14),(13.32,2.14),(13.32,3.8),(13.82,3.8),(13.82,1.44),(13.92,1.44),(13.92,0.12),(13.32,0.12),(13.32,1.78),(12.36,1.78),(12.36,0.12),(11.76,0.12),(11.76,1.78),(11.24,1.78),(11.24,0.12),(10.64,0.12),(10.64,1.78),(9.68,1.78),(9.68,0.12)])
P(gf180mcu_fd_sc_mcu7t5v0_, pplus, [(-0.2,1.76),(-0.2,4.12),(14.76,4.12),(14.76,1.76),(13.39,1.76),(13.39,1.885),(9.61,1.885),(9.61,1.76)])
P(gf180mcu_fd_sc_mcu7t5v0_, nplus, [(-0.2,-0.2),(-0.2,1.76),(9.61,1.76),(9.61,1.885),(13.39,1.885),(13.39,1.76),(14.76,1.76),(14.76,-0.2)])
A(gf180mcu_fd_sc_mcu7t5v0_, contact, 9.155, 1.85, 0.22, 0.22, 8, 1, 0.47, 0)
A(gf180mcu_fd_sc_mcu7t5v0_, contact, 1.27, 2.665, 0.22, 0.22, 4, 2, 2.14, 0.47)
A(gf180mcu_fd_sc_mcu7t5v0_, contact, 2.29, 3.045, 0.22, 0.22, 4, 1, 2.14, 0)
R(gf180mcu_fd_sc_mcu7t5v0_, contact, [(2.39,0.41,2.61,0.63), (6.67,0.41,6.89,0.63), (4.53,0.535,4.75,0.755), (11.39,0.535,11.61,0.755), (14.07,0.535,14.29,0.755), (0.25,0.87,0.47,1.09), (10.05,0.995,10.27,1.215), (12.73,0.995,12.95,1.215), (1.845,1.335,2.065,1.555), (2.915,1.335,3.135,1.555), (6.115,1.335,6.335,1.555), (7.21,1.335,7.43,1.555), (0.765,1.85,0.985,2.07), (3.95,1.85,4.17,2.07), (5.04,1.85,5.26,2.07), (8.205,1.85,8.425,2.07), (10.05,2.665,10.27,2.885), (12.73,2.665,12.95,2.885), (0.25,2.82,0.47,3.04), (13.97,2.82,14.19,3.04), (11.29,3.045,11.51,3.265), (10.05,3.135,10.27,3.355), (12.73,3.135,12.95,3.355), (0.25,3.29,0.47,3.51), (13.97,3.29,14.19,3.51)])
R(gf180mcu_fd_sc_mcu7t5v0_, metal1, [(0.65,1.79,8.53,2.15), (9.05,1.79,12.67,2.13)])
P(gf180mcu_fd_sc_mcu7t5v0_, metal1, [(3.45,1.21),(3.45,1.33),(1.71,1.33),(1.71,1.56),(7.54,1.56),(7.54,1.33),(5.66,1.33),(5.66,1.21)],
  [(9.68,0.99),(9.68,1.22),(12.97,1.22),(12.97,2.38),(1.21,2.38),(1.21,3.36),(1.55,3.36),(1.55,2.755),(3.35,2.755),(3.35,3.36),(3.69,3.36),(3.69,2.755),(5.49,2.755),(5.49,3.36),(5.83,3.36),(5.83,2.755),(7.63,2.755),(7.63,3.36),(7.97,3.36),(7.97,2.755),(9.99,2.755),(9.99,3.36),(10.33,3.36),(10.33,2.755),(12.66,2.755),(12.66,3.36),(13.35,3.36),(13.35,0.99)],
  [(2.945,0.53),(2.945,0.865),(0.18,0.865),(0.18,1.095),(3.175,1.095),(3.175,0.76),(6.135,0.76),(6.135,1.1),(7.98,1.1),(7.98,0.76),(14.36,0.76),(14.36,0.53),(7.75,0.53),(7.75,0.865),(6.365,0.865),(6.365,0.53)],
  [(0,-0.3),(0,0.3),(2.32,0.3),(2.32,0.635),(2.68,0.635),(2.68,0.3),(6.6,0.3),(6.6,0.635),(6.96,0.635),(6.96,0.3),(14.56,0.3),(14.56,-0.3)],
  [(0.245,2.76),(0.245,3.62),(0,3.62),(0,4.22),(14.56,4.22),(14.56,3.62),(14.195,3.62),(14.195,2.76),(13.965,2.76),(13.965,3.62),(11.515,3.62),(11.515,2.985),(11.285,2.985),(11.285,3.62),(8.935,3.62),(8.935,2.985),(8.705,2.985),(8.705,3.62),(6.795,3.62),(6.795,2.985),(6.565,2.985),(6.565,3.62),(4.655,3.62),(4.655,2.985),(4.425,2.985),(4.425,3.62),(2.515,3.62),(2.515,2.985),(2.285,2.985),(2.285,3.62),(0.475,3.62),(0.475,2.76)])
R(gf180mcu_fd_sc_mcu7t5v0_, dualgate, [(-0.28,-0.28,14.84,4.2)])
R(gf180mcu_fd_sc_mcu7t5v0_, v5_xtor, [(0,0,14.56,3.92)])
P(gf180mcu_fd_sc_mcu7t5v0_, lvpwell, [(-0.43,-0.43),(-0.43,1.76),(9.61,1.76),(9.61,1.885),(13.39,1.885),(13.39,1.76),(14.99,1.76),(14.99,-0.43)])
gf180mcu_fd_sc_mcu7t5v0_.add(gdstk.Label('A3', (4.76,1.4), layer=34, texttype=10))
gf180mcu_fd_sc_mcu7t5v0_.add(gdstk.Label('VDD', (7,3.92), layer=34, texttype=10))
gf180mcu_fd_sc_mcu7t5v0_.add(gdstk.Label('VSS', (7,0), layer=34, texttype=10))
gf180mcu_fd_sc_mcu7t5v0_.add(gdstk.Label('ZN', (7.56,2.52), layer=34, texttype=10))
gf180mcu_fd_sc_mcu7t5v0_.add(gdstk.Label('A1', (10.92,1.96), layer=34, texttype=10))
gf180mcu_fd_sc_mcu7t5v0_.add(gdstk.Label('A2', (4.76,1.96), layer=34, texttype=10))
gf180mcu_fd_sc_mcu7t5v0_.add(gdstk.Label('& Vendor GLOBALFOUNDRIES', (0,2), layer=63, texttype=63))
gf180mcu_fd_sc_mcu7t5v0_.add(gdstk.Label('& Product GF018hv5v_mcu_sc7', (0,1.5), layer=63, texttype=63))
gf180mcu_fd_sc_mcu7t5v0_.add(gdstk.Label('& Version 2015q2v1', (0,1), layer=63, texttype=63))
gf180mcu_fd_sc_mcu7t5v0_.add(gdstk.Label('& Metric 1.00', (0,0.5), layer=63, texttype=63))
gf180mcu_fd_sc_mcu7t5v0_.add(gdstk.Label('VNW', (0.345,3.92), layer=21, texttype=10))
gf180mcu_fd_sc_mcu7t5v0_.add(gdstk.Label('VPW', (0.34,-0.085), layer=204, texttype=10))

lib.write_gds('gf180mcu_fd_sc_mcu7t5v0__nand3_4.gds')
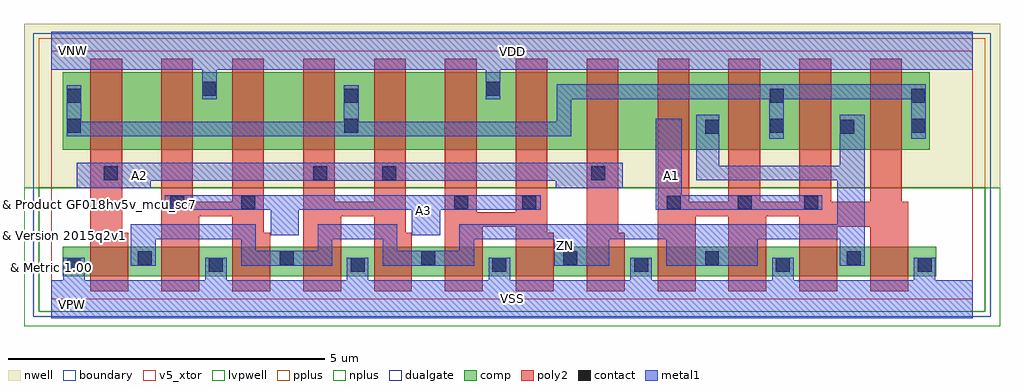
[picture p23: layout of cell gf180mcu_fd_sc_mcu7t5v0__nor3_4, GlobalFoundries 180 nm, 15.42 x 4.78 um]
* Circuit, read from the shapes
.subckt gf180mcu_fd_sc_mcu7t5v0__nor3_4 A1 A2 A3 VDD VNW VSS ZN
XM1 ZN A2 VSS VSUBS nfet_05v0 w=0.465u l=0.6u m=4
XM2 VSS A3 ZN VSUBS nfet_05v0 w=0.465u l=0.6u m=4
XM3 ZN A1 VSS VSUBS nfet_05v0 w=0.465u l=0.6u m=4
XM4 n1 A2 n2 VNW pfet_05v0 w=1.22u l=0.5u
XM5 VDD A3 n1 VNW pfet_05v0 w=1.22u l=0.5u
XM6 n3 A3 VDD VNW pfet_05v0 w=1.22u l=0.5u
XM7 n2 A2 n3 VNW pfet_05v0 w=1.22u l=0.5u
XM8 n4 A2 n2 VNW pfet_05v0 w=1.22u l=0.5u
XM9 VDD A3 n4 VNW pfet_05v0 w=1.22u l=0.5u
XM10 n5 A3 VDD VNW pfet_05v0 w=1.22u l=0.5u
XM11 n6 A2 n5 VNW pfet_05v0 w=1.22u l=0.5u
XM12 ZN A1 n6 VNW pfet_05v0 w=1.22u l=0.5u
XM13 n2 A1 ZN VNW pfet_05v0 w=1.22u l=0.5u m=3
.ends

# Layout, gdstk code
import gdstk
lib = gdstk.Library(unit=1e-6, precision=1e-09)
def R(c, l, rs):  # rectangles x0, y0, x1, y1
    for r in rs: c.add(gdstk.rectangle(r[:2], r[2:], *l))
def A(c, l, x, y, w, h, nx, ny, dx, dy):  # array of equal rectangles
    R(c, l, [(x+i*dx, y+j*dy, x+i*dx+w, y+j*dy+h) for i in range(nx) for j in range(ny)])
def P(c, l, *ps):  # polygons
    for p in ps: c.add(gdstk.Polygon(p, *l))
boundary = (0, 0)
nwell = (21, 0)
comp = (22, 0)
poly2 = (30, 0)
pplus = (31, 0)
nplus = (32, 0)
contact = (33, 0)
metal1 = (34, 0)
dualgate = (55, 0)
v5_xtor = (112, 1)
lvpwell = (204, 0)

gf180mcu_fd_sc_mcu7t5v0_ = lib.new_cell('gf180mcu_fd_sc_mcu7t5v0__nor3_4')
R(gf180mcu_fd_sc_mcu7t5v0_, boundary, [(0,0,14.56,3.92)])
R(gf180mcu_fd_sc_mcu7t5v0_, nwell, [(-0.43,1.76,14.99,4.35)])
R(gf180mcu_fd_sc_mcu7t5v0_, comp, [(0.18,0.36,13.98,0.825), (0.18,2.36,13.88,3.58)])
P(gf180mcu_fd_sc_mcu7t5v0_, poly2, [(0.62,0.12),(0.62,3.8),(1.12,3.8),(1.12,1.045),(1.22,1.045),(1.22,0.12)],
  [(1.74,0.12),(1.74,3.8),(2.24,3.8),(2.24,1.535),(2.86,1.535),(2.86,3.8),(3.36,3.8),(3.36,1.045),(3.46,1.045),(3.46,0.12),(2.86,0.12),(2.86,1.305),(2.34,1.305),(2.34,0.12)],
  [(3.98,0.12),(3.98,3.8),(4.48,3.8),(4.48,1.535),(5.1,1.535),(5.1,3.8),(5.6,3.8),(5.6,1.045),(5.7,1.045),(5.7,0.12),(5.1,0.12),(5.1,1.305),(4.58,1.305),(4.58,0.12)],
  [(6.22,0.12),(6.22,3.8),(6.72,3.8),(6.72,1.37),(7.34,1.37),(7.34,3.8),(7.84,3.8),(7.84,1.045),(7.94,1.045),(7.94,0.12),(7.34,0.12),(7.34,1.14),(6.82,1.14),(6.82,0.12)],
  [(8.46,0.12),(8.46,3.8),(8.96,3.8),(8.96,1.045),(9.06,1.045),(9.06,0.12)],
  [(9.58,0.12),(9.58,3.8),(10.08,3.8),(10.08,1.535),(10.7,1.535),(10.7,3.8),(11.2,3.8),(11.2,1.535),(11.82,1.535),(11.82,3.8),(12.32,3.8),(12.32,1.535),(12.94,1.535),(12.94,3.8),(13.44,3.8),(13.44,1.535),(13.54,1.535),(13.54,0.12),(12.94,0.12),(12.94,1.14),(12.42,1.14),(12.42,0.12),(11.82,0.12),(11.82,1.305),(11.3,1.305),(11.3,0.12),(10.7,0.12),(10.7,1.305),(10.18,1.305),(10.18,0.12)])
R(gf180mcu_fd_sc_mcu7t5v0_, pplus, [(-0.2,1.76,14.76,4.12)])
R(gf180mcu_fd_sc_mcu7t5v0_, nplus, [(-0.2,-0.2,14.76,1.76)])
A(gf180mcu_fd_sc_mcu7t5v0_, contact, 0.25, 0.43, 0.22, 0.22, 7, 1, 2.24, 0)
A(gf180mcu_fd_sc_mcu7t5v0_, contact, 1.37, 0.535, 0.22, 0.22, 6, 1, 2.24, 0)
R(gf180mcu_fd_sc_mcu7t5v0_, contact, [(1.88,1.415,2.1,1.635), (3,1.415,3.22,1.635), (6.365,1.415,6.585,1.635), (7.44,1.415,7.66,1.635), (9.725,1.415,9.945,1.635), (10.845,1.415,11.065,1.635), (11.9,1.415,12.12,1.635), (4.14,1.875,4.36,2.095), (5.23,1.875,5.45,2.095), (0.83,1.88,1.05,2.1), (8.53,1.88,8.75,2.1), (10.33,2.61,10.55,2.83), (12.47,2.61,12.69,2.83), (0.25,2.63,0.47,2.85), (4.63,2.63,4.85,2.85), (11.35,2.63,11.57,2.85), (13.59,2.63,13.81,2.85), (0.25,3.1,0.47,3.32), (4.63,3.1,4.85,3.32), (11.35,3.1,11.57,3.32), (13.59,3.1,13.81,3.32), (2.39,3.215,2.61,3.435), (6.87,3.215,7.09,3.435)])
P(gf180mcu_fd_sc_mcu7t5v0_, metal1, [(3.47,1.01),(3.47,1.41),(1.79,1.41),(1.79,1.64),(7.735,1.64),(7.735,1.41),(6.15,1.41),(6.15,1.01),(5.7,1.01),(5.7,1.41),(3.91,1.41),(3.91,1.01)],
  [(0.405,1.75),(0.405,2.15),(9.03,2.15),(9.03,1.75),(7.97,1.75),(7.97,1.87),(1.57,1.87),(1.57,1.75)],
  [(9.55,1.41),(9.55,2.85),(9.96,2.85),(9.96,1.64),(12.18,1.64),(12.18,1.41)],
  [(1.255,0.53),(1.255,1.18),(3.23,1.18),(3.23,0.76),(4.21,0.76),(4.21,1.18),(5.47,1.18),(5.47,0.76),(6.45,0.76),(6.45,1.18),(12.42,1.18),(12.42,1.875),(10.19,1.875),(10.19,2.91),(10.555,2.91),(10.555,2.11),(12.46,2.11),(12.46,2.91),(12.85,2.91),(12.85,0.53),(12.46,0.53),(12.46,0.945),(11.16,0.945),(11.16,0.53),(9.72,0.53),(9.72,0.945),(8.82,0.945),(8.82,0.53),(7.95,0.53),(7.95,0.945),(6.68,0.945),(6.68,0.53),(5.24,0.53),(5.24,0.945),(4.44,0.945),(4.44,0.53),(3,0.53),(3,0.945),(1.65,0.945),(1.65,0.53)],
  [(11.345,2.53),(11.345,3.16),(8.22,3.16),(8.22,2.57),(0.245,2.57),(0.245,3.38),(0.475,3.38),(0.475,2.8),(4.625,2.8),(4.625,3.38),(4.855,3.38),(4.855,2.8),(7.99,2.8),(7.99,3.39),(13.815,3.39),(13.815,2.53),(13.585,2.53),(13.585,3.16),(11.575,3.16),(11.575,2.53)],
  [(0,-0.3),(0,0.3),(0.19,0.3),(0.19,0.655),(0.53,0.655),(0.53,0.3),(2.43,0.3),(2.43,0.655),(2.77,0.655),(2.77,0.3),(4.67,0.3),(4.67,0.655),(5.01,0.655),(5.01,0.3),(6.91,0.3),(6.91,0.655),(7.25,0.655),(7.25,0.3),(9.15,0.3),(9.15,0.655),(9.49,0.655),(9.49,0.3),(11.39,0.3),(11.39,0.655),(11.73,0.655),(11.73,0.3),(13.63,0.3),(13.63,0.655),(13.97,0.655),(13.97,0.3),(14.56,0.3),(14.56,-0.3)],
  [(2.385,3.155),(2.385,3.62),(0,3.62),(0,4.22),(14.56,4.22),(14.56,3.62),(7.095,3.62),(7.095,3.155),(6.865,3.155),(6.865,3.62),(2.615,3.62),(2.615,3.155)])
R(gf180mcu_fd_sc_mcu7t5v0_, dualgate, [(-0.28,-0.28,14.84,4.2)])
R(gf180mcu_fd_sc_mcu7t5v0_, v5_xtor, [(0,0,14.56,3.92)])
R(gf180mcu_fd_sc_mcu7t5v0_, lvpwell, [(-0.43,-0.43,14.99,1.76)])
gf180mcu_fd_sc_mcu7t5v0_.add(gdstk.Label('A3', (5.88,1.4), layer=34, texttype=10))
gf180mcu_fd_sc_mcu7t5v0_.add(gdstk.Label('VDD', (7.28,3.905), layer=34, texttype=10))
gf180mcu_fd_sc_mcu7t5v0_.add(gdstk.Label('VSS', (7.28,0.01), layer=34, texttype=10))
gf180mcu_fd_sc_mcu7t5v0_.add(gdstk.Label('ZN', (8.12,0.84), layer=34, texttype=10))
gf180mcu_fd_sc_mcu7t5v0_.add(gdstk.Label('A1', (9.8,1.96), layer=34, texttype=10))
gf180mcu_fd_sc_mcu7t5v0_.add(gdstk.Label('A2', (1.4,1.96), layer=34, texttype=10))
gf180mcu_fd_sc_mcu7t5v0_.add(gdstk.Label('& Vendor GLOBALFOUNDRIES', (0,2), layer=63, texttype=63))
gf180mcu_fd_sc_mcu7t5v0_.add(gdstk.Label('& Product GF018hv5v_mcu_sc7', (0,1.5), layer=63, texttype=63))
gf180mcu_fd_sc_mcu7t5v0_.add(gdstk.Label('& Version 2015q2v1', (0,1), layer=63, texttype=63))
gf180mcu_fd_sc_mcu7t5v0_.add(gdstk.Label('& Metric 1.00', (0,0.5), layer=63, texttype=63))
gf180mcu_fd_sc_mcu7t5v0_.add(gdstk.Label('VNW', (0.345,3.92), layer=21, texttype=10))
gf180mcu_fd_sc_mcu7t5v0_.add(gdstk.Label('VPW', (0.34,-0.085), layer=204, texttype=10))

lib.write_gds('gf180mcu_fd_sc_mcu7t5v0__nor3_4.gds')
